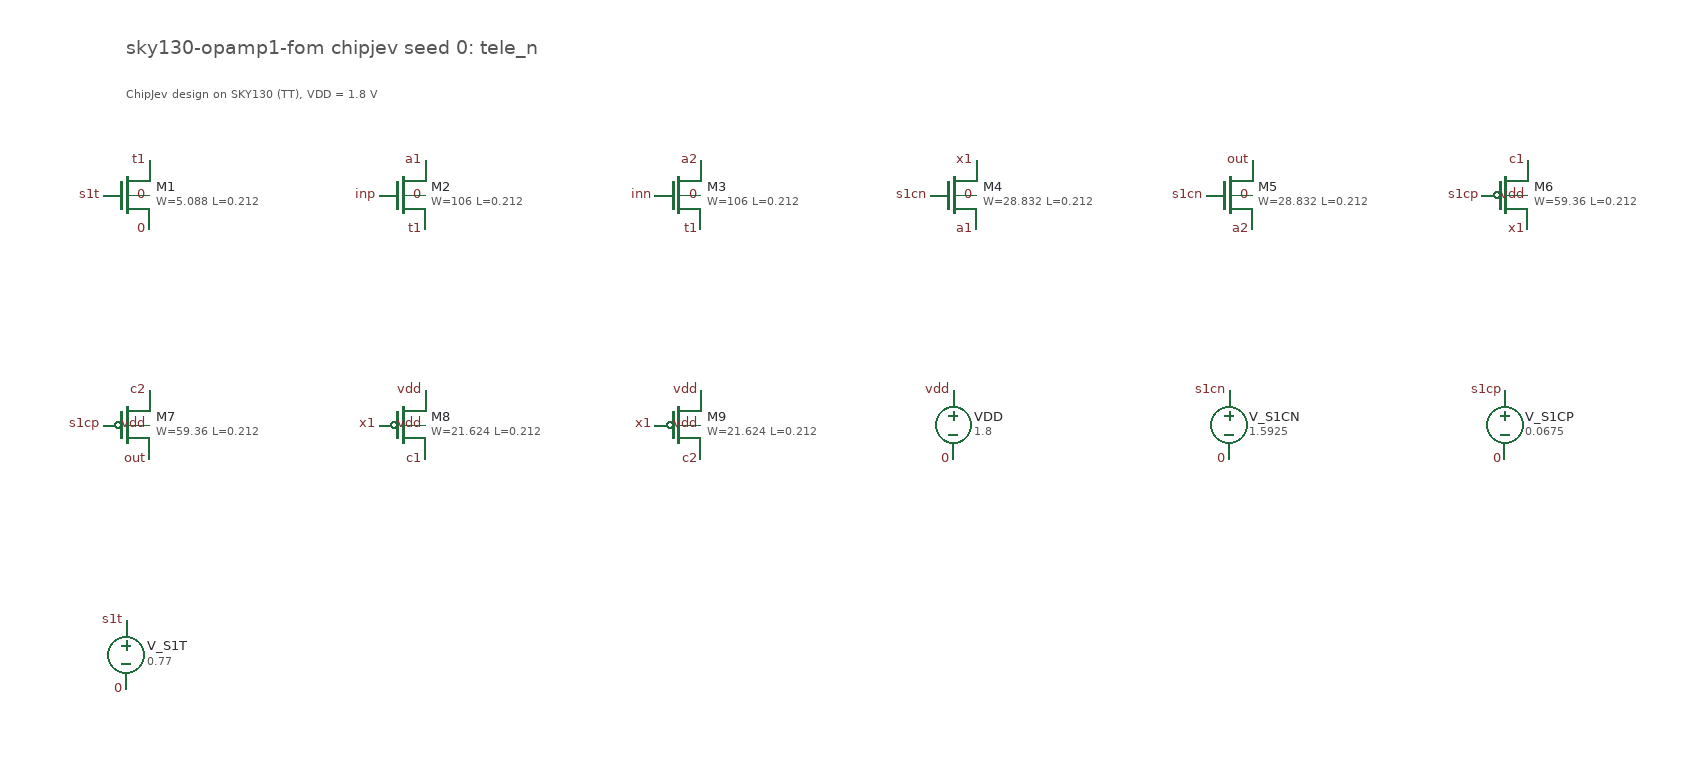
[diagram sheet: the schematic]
v {xschem version=3.4.5 file_version=1.2}
G {}
K {}
V {}
S {}
E {}
T {sky130-opamp1-fom chipjev seed 0: tele_n} 0 -140 0 0 0.5 0.5 {}
T {ChipJev design on SKY130 (TT), VDD = 1.8 V} 0 -100 0 0 0.3 0.3 {}
C {sky130_fd_pr/nfet_01v8.sym} 0 0 0 0 {name=M1 L=0.212 W=5.088 nf=1 mult=1 ad=1.47552 as=1.47552 pd=10.756 ps=10.756 nrd=0.0569969 nrs=0.0569969 sa=0 sb=0 sd=0 model=nfet_01v8 spiceprefix=X}
C {devices/lab_pin.sym} 20 -30 0 0 {name=l1 sig_type=std_logic lab=t1}
C {devices/lab_pin.sym} -20 0 0 0 {name=l2 sig_type=std_logic lab=s1t}
C {devices/lab_pin.sym} 20 30 0 0 {name=l3 sig_type=std_logic lab=0}
C {devices/lab_pin.sym} 20 0 0 0 {name=l4 sig_type=std_logic lab=0}
C {sky130_fd_pr/nfet_01v8.sym} 240 0 0 0 {name=M2 L=0.212 W=106 nf=3 mult=1 ad=20.4933 as=20.4933 pd=142.493 ps=142.493 nrd=0.00273585 nrs=0.00273585 sa=0 sb=0 sd=0 model=nfet_01v8 spiceprefix=X}
C {devices/lab_pin.sym} 260 -30 0 0 {name=l5 sig_type=std_logic lab=a1}
C {devices/lab_pin.sym} 220 0 0 0 {name=l6 sig_type=std_logic lab=inp}
C {devices/lab_pin.sym} 260 30 0 0 {name=l7 sig_type=std_logic lab=t1}
C {devices/lab_pin.sym} 260 0 0 0 {name=l8 sig_type=std_logic lab=0}
C {sky130_fd_pr/nfet_01v8.sym} 480 0 0 0 {name=M3 L=0.212 W=106 nf=3 mult=1 ad=20.4933 as=20.4933 pd=142.493 ps=142.493 nrd=0.00273585 nrs=0.00273585 sa=0 sb=0 sd=0 model=nfet_01v8 spiceprefix=X}
C {devices/lab_pin.sym} 500 -30 0 0 {name=l9 sig_type=std_logic lab=a2}
C {devices/lab_pin.sym} 460 0 0 0 {name=l10 sig_type=std_logic lab=inn}
C {devices/lab_pin.sym} 500 30 0 0 {name=l11 sig_type=std_logic lab=t1}
C {devices/lab_pin.sym} 500 0 0 0 {name=l12 sig_type=std_logic lab=0}
C {sky130_fd_pr/nfet_01v8.sym} 720 0 0 0 {name=M4 L=0.212 W=28.832 nf=1 mult=1 ad=8.36128 as=8.36128 pd=58.244 ps=58.244 nrd=0.0100583 nrs=0.0100583 sa=0 sb=0 sd=0 model=nfet_01v8 spiceprefix=X}
C {devices/lab_pin.sym} 740 -30 0 0 {name=l13 sig_type=std_logic lab=x1}
C {devices/lab_pin.sym} 700 0 0 0 {name=l14 sig_type=std_logic lab=s1cn}
C {devices/lab_pin.sym} 740 30 0 0 {name=l15 sig_type=std_logic lab=a1}
C {devices/lab_pin.sym} 740 0 0 0 {name=l16 sig_type=std_logic lab=0}
C {sky130_fd_pr/nfet_01v8.sym} 960 0 0 0 {name=M5 L=0.212 W=28.832 nf=1 mult=1 ad=8.36128 as=8.36128 pd=58.244 ps=58.244 nrd=0.0100583 nrs=0.0100583 sa=0 sb=0 sd=0 model=nfet_01v8 spiceprefix=X}
C {devices/lab_pin.sym} 980 -30 0 0 {name=l17 sig_type=std_logic lab=out}
C {devices/lab_pin.sym} 940 0 0 0 {name=l18 sig_type=std_logic lab=s1cn}
C {devices/lab_pin.sym} 980 30 0 0 {name=l19 sig_type=std_logic lab=a2}
C {devices/lab_pin.sym} 980 0 0 0 {name=l20 sig_type=std_logic lab=0}
C {sky130_fd_pr/pfet_01v8.sym} 1200 0 0 0 {name=M6 L=0.212 W=59.36 nf=2 mult=1 ad=8.6072 as=17.2144 pd=59.94 ps=119.88 nrd=0.00488544 nrs=0.00488544 sa=0 sb=0 sd=0 model=pfet_01v8 spiceprefix=X}
C {devices/lab_pin.sym} 1220 30 0 0 {name=l21 sig_type=std_logic lab=x1}
C {devices/lab_pin.sym} 1180 0 0 0 {name=l22 sig_type=std_logic lab=s1cp}
C {devices/lab_pin.sym} 1220 -30 0 0 {name=l23 sig_type=std_logic lab=c1}
C {devices/lab_pin.sym} 1220 0 0 0 {name=l24 sig_type=std_logic lab=vdd}
C {sky130_fd_pr/pfet_01v8.sym} 0 200 0 0 {name=M7 L=0.212 W=59.36 nf=2 mult=1 ad=8.6072 as=17.2144 pd=59.94 ps=119.88 nrd=0.00488544 nrs=0.00488544 sa=0 sb=0 sd=0 model=pfet_01v8 spiceprefix=X}
C {devices/lab_pin.sym} 20 230 0 0 {name=l25 sig_type=std_logic lab=out}
C {devices/lab_pin.sym} -20 200 0 0 {name=l26 sig_type=std_logic lab=s1cp}
C {devices/lab_pin.sym} 20 170 0 0 {name=l27 sig_type=std_logic lab=c2}
C {devices/lab_pin.sym} 20 200 0 0 {name=l28 sig_type=std_logic lab=vdd}
C {sky130_fd_pr/pfet_01v8.sym} 240 200 0 0 {name=M8 L=0.212 W=21.624 nf=1 mult=1 ad=6.27096 as=6.27096 pd=43.828 ps=43.828 nrd=0.013411 nrs=0.013411 sa=0 sb=0 sd=0 model=pfet_01v8 spiceprefix=X}
C {devices/lab_pin.sym} 260 230 0 0 {name=l29 sig_type=std_logic lab=c1}
C {devices/lab_pin.sym} 220 200 0 0 {name=l30 sig_type=std_logic lab=x1}
C {devices/lab_pin.sym} 260 170 0 0 {name=l31 sig_type=std_logic lab=vdd}
C {devices/lab_pin.sym} 260 200 0 0 {name=l32 sig_type=std_logic lab=vdd}
C {sky130_fd_pr/pfet_01v8.sym} 480 200 0 0 {name=M9 L=0.212 W=21.624 nf=1 mult=1 ad=6.27096 as=6.27096 pd=43.828 ps=43.828 nrd=0.013411 nrs=0.013411 sa=0 sb=0 sd=0 model=pfet_01v8 spiceprefix=X}
C {devices/lab_pin.sym} 500 230 0 0 {name=l33 sig_type=std_logic lab=c2}
C {devices/lab_pin.sym} 460 200 0 0 {name=l34 sig_type=std_logic lab=x1}
C {devices/lab_pin.sym} 500 170 0 0 {name=l35 sig_type=std_logic lab=vdd}
C {devices/lab_pin.sym} 500 200 0 0 {name=l36 sig_type=std_logic lab=vdd}
C {devices/vsource.sym} 720 200 0 0 {name=VDD value=1.8 m=1}
C {devices/lab_pin.sym} 720 170 0 0 {name=l37 sig_type=std_logic lab=vdd}
C {devices/lab_pin.sym} 720 230 0 0 {name=l38 sig_type=std_logic lab=0}
C {devices/vsource.sym} 960 200 0 0 {name=V_S1CN value=1.5925 m=1}
C {devices/lab_pin.sym} 960 170 0 0 {name=l39 sig_type=std_logic lab=s1cn}
C {devices/lab_pin.sym} 960 230 0 0 {name=l40 sig_type=std_logic lab=0}
C {devices/vsource.sym} 1200 200 0 0 {name=V_S1CP value=0.0675 m=1}
C {devices/lab_pin.sym} 1200 170 0 0 {name=l41 sig_type=std_logic lab=s1cp}
C {devices/lab_pin.sym} 1200 230 0 0 {name=l42 sig_type=std_logic lab=0}
C {devices/vsource.sym} 0 400 0 0 {name=V_S1T value=0.77 m=1}
C {devices/lab_pin.sym} 0 370 0 0 {name=l43 sig_type=std_logic lab=s1t}
C {devices/lab_pin.sym} 0 430 0 0 {name=l44 sig_type=std_logic lab=0}
